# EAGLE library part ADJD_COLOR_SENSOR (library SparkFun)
Color Light Sensor ADJD-S371 from Avago. Digital RGB light sensor (I2C) with on-board white LED. Not quite proven footprint or schematic component. SKU: COM-08618

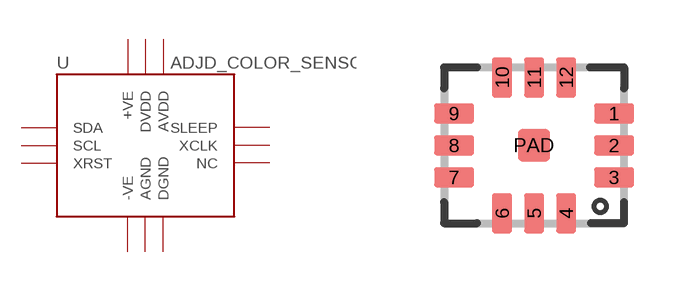
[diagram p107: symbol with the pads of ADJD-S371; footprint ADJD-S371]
Designator prefix -

## ADJD_COLOR_SENSOR_SMD  [ADJD-S371]
1  -VE
2  NC
3  +VE
4  SDA
5  DVDD
6  SCL
7  AVDD
8  SLEEP
9  AGND
10  XRST
11  DGND
12  XCLK

## Footprint ADJD-S371 (pad centres in mm)
smd 1 x 0.5: 1 2,0.8; 2 2,0; 3 2,-0.8; 7 -2,-0.8; 8 -2,0; 9 -2,0.8
smd 0.5 x 1: 4 0.8,-1.7; 5 0,-1.7; 6 -0.8,-1.7; 10 -0.8,1.7; 11 0,1.7; 12 0.8,1.7
smd 0.8 x 0.8: PAD 0,0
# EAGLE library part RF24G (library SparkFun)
RF24G Header This is the header for connections to the RF24G Transceiver (SparkFun Electronics SKU: WRL-00151), used in the Breakout Board for RF24G Transceiver (SparkFun Electronics SKU: BOB-00196). This footprint has not yet been proven in production.

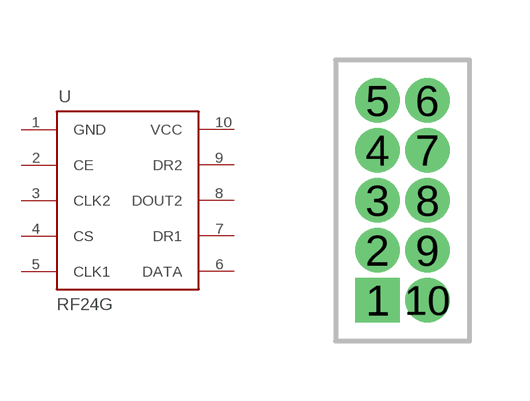
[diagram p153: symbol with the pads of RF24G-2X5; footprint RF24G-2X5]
Designator prefix -

## RF24G  [RF24G-2X5]
1  GND
2  CE
3  CLK2
4  CS
5  CLK1
6  DATA
7  DR1
8  DOUT2
9  DR2
10  VCC

## Footprint RF24G-2X5 (pad centres in mm)
test
drill 0.6 pad 0.965 square: 1 1.047,1.021
drill 0.6 pad 0.965 round: 2 1.047,2.271; 3 1.047,3.521; 4 1.047,4.771; 5 1.047,6.021; 6 2.297,6.021; 7 2.297,4.771; 8 2.297,3.521; 9 2.297,2.271; 10 2.297,1.021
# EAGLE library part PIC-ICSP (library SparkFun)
ISCP Programming connector for UAV, UBW Kit, etc.

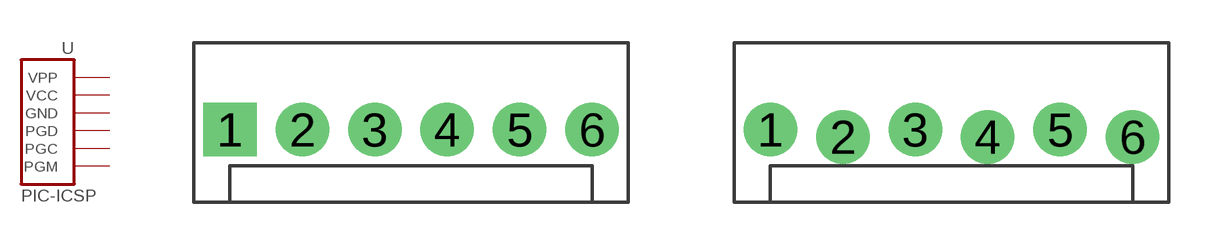
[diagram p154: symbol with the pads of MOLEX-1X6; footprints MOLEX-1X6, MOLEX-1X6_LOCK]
Designator prefix -

## PIC-ICSPPTH  [MOLEX-1X6]
1  PGM
2  PGC
3  PGD
4  GND
5  VCC
6  VPP

## PIC-ICSPPOLAR_LOCK  [MOLEX-1X6_LOCK]
Pads as for MOLEX-1X6

## Footprint MOLEX-1X6 (pad centres in mm)
drill 1.016 pad 1.88 square: 1 0,0
drill 1.016 pad 1.88 round: 2 2.54,0; 3 5.08,0; 4 7.62,0; 5 10.16,0; 6 12.7,0

## Footprint MOLEX-1X6_LOCK (pad centres in mm)
This footprint was designed to help hold the alignment of a through-hole component (i.e. 6-pin header) while soldering it into place. You may notice that each hole has been shifted either up or down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
drill 1.016 pad 1.88 round: 1 0,0; 2 2.54,-0.254; 3 5.08,0; 4 7.62,-0.254; 5 10.16,0; 6 12.7,-0.254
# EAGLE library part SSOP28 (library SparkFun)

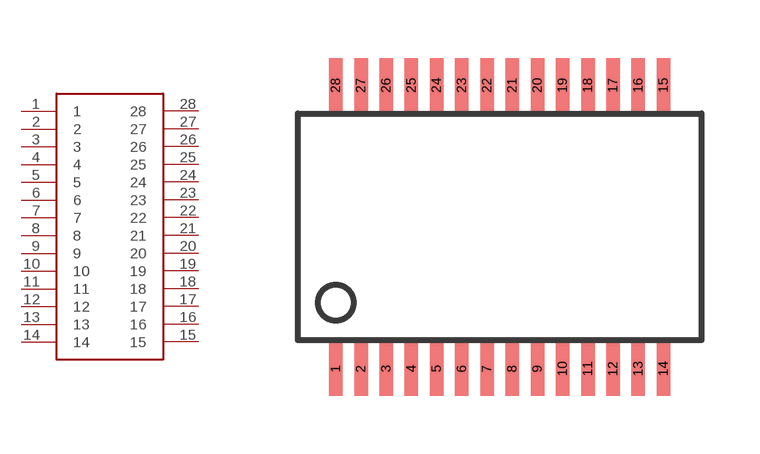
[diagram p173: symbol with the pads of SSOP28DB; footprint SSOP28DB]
Designator prefix -

## SSOP28  [SSOP28DB]
1  1
2  2
3  3
4  4
5  5
6  6
7  7
8  8
9  9
10  10
11  11
12  12
13  13
14  14
15  15
16  16
17  17
18  18
19  19
20  20
21  21
22  22
23  23
24  24
25  25
26  26
27  27
28  28

## Footprint SSOP28DB (pad centres in mm)
Small Shrink Outline Package
smd 0.348 x 1.397: 1 -4.225,-3.656; 2 -3.575,-3.656; 3 -2.925,-3.656; 4 -2.275,-3.656; 5 -1.625,-3.656; 6 -0.975,-3.656; 7 -0.325,-3.656; 8 0.325,-3.656; 9 0.975,-3.656; 10 1.625,-3.656; 11 2.275,-3.656; 12 2.925,-3.656; 13 3.575,-3.656; 14 4.225,-3.656; 15 4.225,3.656; 16 3.575,3.656; 17 2.925,3.656; 18 2.275,3.656; 19 1.625,3.656; 20 0.975,3.656; 21 0.325,3.656; 22 -0.325,3.656; 23 -0.975,3.656; 24 -1.625,3.656; 25 -2.275,3.656; 26 -2.925,3.656; 27 -3.575,3.656; 28 -4.225,3.656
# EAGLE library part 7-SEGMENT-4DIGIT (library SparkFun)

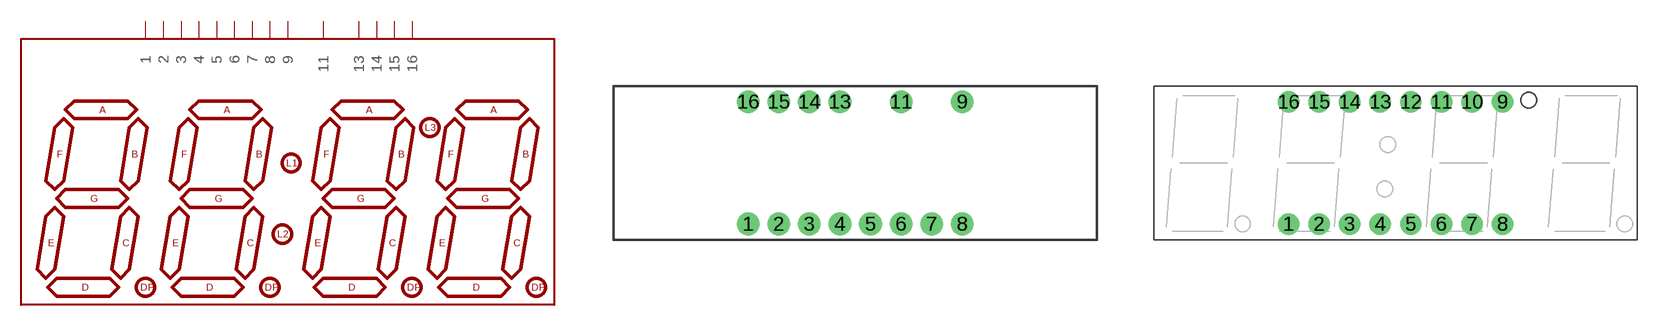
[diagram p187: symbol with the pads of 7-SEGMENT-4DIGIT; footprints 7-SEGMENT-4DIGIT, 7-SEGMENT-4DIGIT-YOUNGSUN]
Designator prefix -

## 7-SEGMENT-4DIGITPTH  [7-SEGMENT-4DIGIT]
1  1
2  2
3  3
4  4
5  5
6  6
7  7
8  8
9  9
11  11
13  13
14  14
15  15
16  16

## 7-SEGMENT-4DIGIT  [7-SEGMENT-4DIGIT-YOUNGSUN]
Pads as for 7-SEGMENT-4DIGIT

## 7-SEGMENT-4DIGITFOR_POGOBED_ONLY  [7-SEGMENT-4DIGIT_LONGPADS_FOR_POGOBED]
Pads as for 7-SEGMENT-4DIGIT

## Footprint 7-SEGMENT-4DIGIT (pad centres in mm)
drill 0.9 pad 1.88 round: 1 -8.89,-5.08; 2 -6.35,-5.08; 3 -3.81,-5.08; 4 -1.27,-5.08; 5 1.27,-5.08; 6 3.81,-5.08; 7 6.35,-5.08; 8 8.89,-5.08; 9 8.89,5.08; 11 3.81,5.08; 13 -1.27,5.08; 14 -3.81,5.08; 15 -6.35,5.08; 16 -8.89,5.08

## Footprint 7-SEGMENT-4DIGIT-YOUNGSUN (pad centres in mm)
This is a package for the 4-digit 7-segment RED LED from Young Sun.
drill 0.8 pad 1.778 round: 1 -8.89,-5.08; 2 -6.35,-5.08; 3 -3.81,-5.08; 4 -1.27,-5.08; 5 1.27,-5.08; 6 3.81,-5.08; 7 6.35,-5.08; 8 8.89,-5.08; 9 8.89,5.08; 10 6.35,5.08; 11 3.81,5.08; 12 1.27,5.08; 13 -1.27,5.08; 14 -3.81,5.08; 15 -6.35,5.08; 16 -8.89,5.08

## Footprint 7-SEGMENT-4DIGIT_LONGPADS_FOR_POGOBED (pad centres in mm)
drill 1.016 pad 1.88 long: 1 -8.89,-5.08; 2 -6.35,-5.08; 3 -3.81,-5.08; 4 -1.27,-5.08; 5 1.27,-5.08; 6 3.81,-5.08; 7 6.35,-5.08; 8 8.89,-5.08; 9 8.89,5.08; 11 3.81,5.08; 13 -1.27,5.08; 14 -3.81,5.08; 15 -6.35,5.08; 16 -8.89,5.08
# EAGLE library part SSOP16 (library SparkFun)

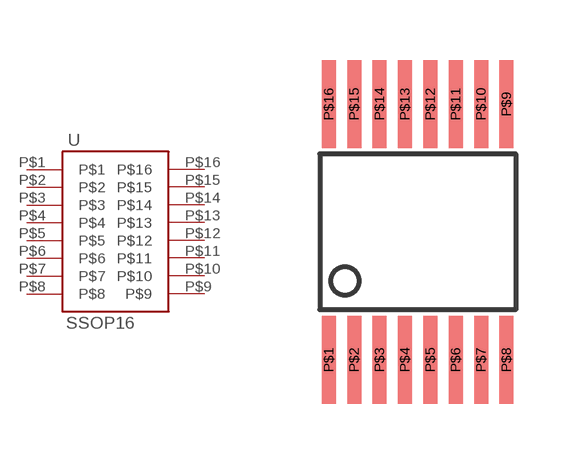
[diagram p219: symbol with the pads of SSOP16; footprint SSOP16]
Designator prefix -

## SSOP16  [SSOP16]
P$1  P$1
P$2  P$2
P$3  P$3
P$4  P$4
P$5  P$5
P$6  P$6
P$7  P$7
P$8  P$8
P$9  P$9
P$10  P$10
P$11  P$11
P$12  P$12
P$13  P$13
P$14  P$14
P$15  P$15
P$16  P$16

## Footprint SSOP16 (pad centres in mm)
smd 0.35 x 2.2: P$1 -2.223,-3.2; P$2 -1.587,-3.2; P$3 -0.953,-3.2; P$4 -0.318,-3.2; P$5 0.318,-3.2; P$6 0.953,-3.2; P$7 1.587,-3.2; P$8 2.223,-3.2; P$9 2.223,3.2; P$10 1.587,3.2; P$11 0.953,3.2; P$12 0.318,3.2; P$13 -0.318,3.2; P$14 -0.953,3.2; P$15 -1.587,3.2; P$16 -2.223,3.2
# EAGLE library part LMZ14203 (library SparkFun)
LMZ14203 3A, Simple Switcher Power Module with 42V Maximum Input

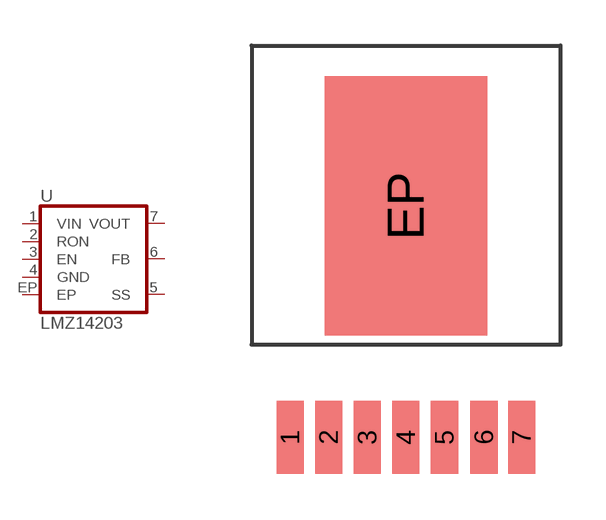
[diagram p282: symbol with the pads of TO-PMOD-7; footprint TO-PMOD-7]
Designator prefix U

## LMZ14203  [TO-PMOD-7]
1  VIN
2  RON
3  EN
4  GND
5  SS
6  FB
7  VOUT
EP  EP

## Footprint TO-PMOD-7 (pad centres in mm)
7-Lead package for National voltage switchers (LMZ14203)
smd 0.89 x 2.41: 1 -3.81,-7.63; 2 -2.54,-7.63; 3 -1.27,-7.63; 4 0,-7.63; 5 1.27,-7.63; 6 2.57,-7.63; 7 3.81,-7.63
smd 5.35 x 8.54: EP 0,0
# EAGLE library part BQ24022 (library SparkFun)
TI BQ24022 Single-chip, Li-ion and Li-pol charger IC with autonomous USB-port and AC-adapter supply management. Datasheet: http://focus.ti.com/lit/ds/symlink/bq24022.pdf Unproven Last modified: 8/16/10

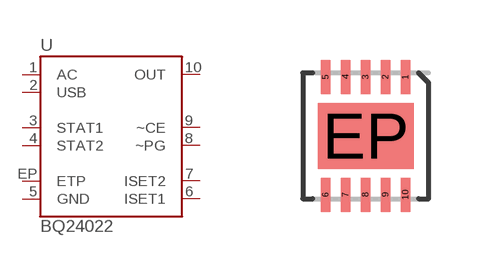
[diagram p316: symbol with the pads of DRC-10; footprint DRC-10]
Designator prefix U

## BQ24022  [DRC-10]
1  AC
2  USB
3  STAT1
4  STAT2
5  GND
6  ISET1
7  ISET2
8  ~PG
9  ~CE
10  OUT
EP  ETP

## Footprint DRC-10 (pad centres in mm)
10-pin QFN/SON package Package Type: SON Package Drawing: DRC Pitch: 0.5mm Overall Dimensions: 3.15x3.15mm Pins: 10 (+1 exposed heatsink pin) Related ICs: TI's BQ2402x -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
smd 0.23 x 0.85: 1 1,1.475; 2 0.5,1.475; 3 0,1.475; 4 -0.5,1.475; 5 -1,1.475; 6 -1,-1.475; 7 -0.5,-1.475; 8 0,-1.475; 9 0.5,-1.475; 10 1,-1.475
smd 2.4 x 1.65: EP 0,0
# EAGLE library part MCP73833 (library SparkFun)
Microchip MCP73833 Stand-alone Linear Li-ion/Li-polymer Charge Management Controller Packages: DFN-10, MSOP-10 Last modified: 8/17/10 Unproven!

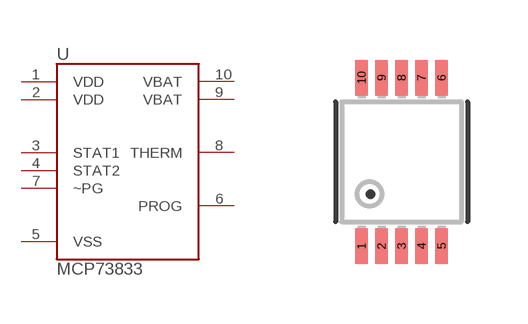
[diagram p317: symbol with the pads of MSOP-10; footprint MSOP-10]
Designator prefix U

## MCP73833  [MSOP-10]
1  VDD
2  VDD
3  STAT1
4  STAT2
5  VSS
6  PROG
7  ~PG
8  THERM
9  VBAT
10  VBAT

## Footprint MSOP-10 (pad centres in mm)
smd 0.305 x 0.889: 1 -1,-2.11; 2 -0.5,-2.11; 3 0,-2.11; 4 0.5,-2.11; 5 1,-2.11; 6 1,2.11; 7 0.5,2.11; 8 0,2.11; 9 -0.5,2.11; 10 -1,2.11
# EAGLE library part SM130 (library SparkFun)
13.56MHz RFID Mifare Read/Write Module

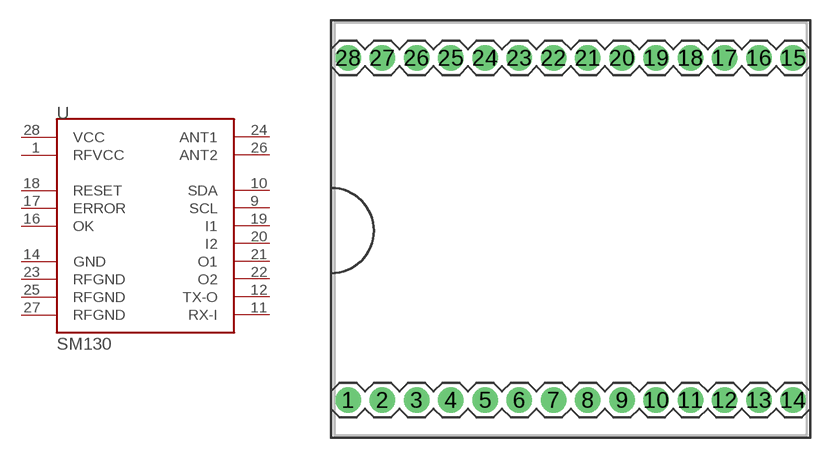
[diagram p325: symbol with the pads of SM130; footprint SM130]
Designator prefix U

## SM130  [SM130]
1  RFVCC
9  SCL
10  SDA
11  RX-I
12  TX-O
14  GND
16  OK
17  ERROR
18  RESET
19  I1
20  I2
21  O1
22  O2
23  RFGND
24  ANT1
25  RFGND
26  ANT2
27  RFGND
28  VCC

## Footprint SM130 (pad centres in mm)
30-pin DIL with 100mil spacing between headers
drill 1.016 pad 1.88 round: 1 -17.78,-12.7; 2 -15.24,-12.7; 3 -12.7,-12.7; 4 -10.16,-12.7; 5 -7.62,-12.7; 6 -5.08,-12.7; 7 -2.54,-12.7; 8 0,-12.7; 9 2.54,-12.7; 10 5.08,-12.7; 11 7.62,-12.7; 12 10.16,-12.7; 13 12.7,-12.7; 14 15.24,-12.7; 15 15.24,12.7; 16 12.7,12.7; 17 10.16,12.7; 18 7.62,12.7; 19 5.08,12.7; 20 2.54,12.7; 21 0,12.7; 22 -2.54,12.7; 23 -5.08,12.7; 24 -7.62,12.7; 25 -10.16,12.7; 26 -12.7,12.7; 27 -15.24,12.7; 28 -17.78,12.7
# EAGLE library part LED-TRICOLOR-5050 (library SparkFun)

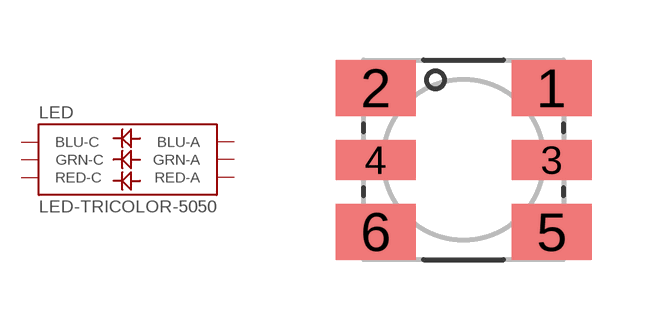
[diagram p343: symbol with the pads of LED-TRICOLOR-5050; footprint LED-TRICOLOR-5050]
Designator prefix LED

## LED-TRICOLOR-5050  [LED-TRICOLOR-5050]
1  GRN-A
2  RED-A
3  BLU-A
4  BLU-C
5  RED-C
6  GRN-C

## Footprint LED-TRICOLOR-5050 (pad centres in mm)
5050 SMD RGB LED 5.0mm x 5.0mm, 2.6mm thickness
smd 2 x 1.4: 1 2.2,1.8; 2 -2.2,1.8; 5 2.2,-1.8; 6 -2.2,-1.8
smd 2 x 1: 3 2.2,0; 4 -2.2,0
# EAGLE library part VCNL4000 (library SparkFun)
VNCL4000 Fully integrated proximity and ambient light sensor with infrared emitter and I2C interface

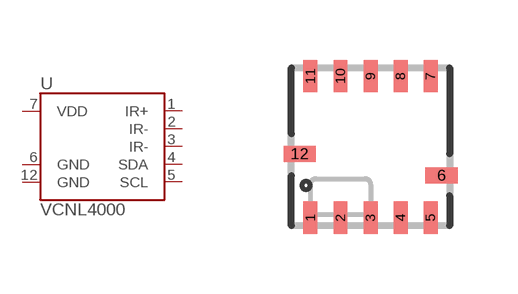
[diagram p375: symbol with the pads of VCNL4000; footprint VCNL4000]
Designator prefix U

## VCNL4000  [VCNL4000]
1  IR+
2  IR-
3  IR-
4  SDA
5  SCL
6  GND
7  VDD
12  GND

## Footprint VCNL4000 (pad centres in mm)
VCNL4000 Footprint For Vishay VNCL4000 proximity and ambient light sensor. Unproven
smd 0.35 x 0.805: 1 -1.5,-1.772; 2 -0.75,-1.772; 3 0,-1.772; 4 0.75,-1.772; 5 1.5,-1.772; 7 1.5,1.772; 8 0.75,1.772; 9 0,1.772; 10 -0.75,1.772; 11 -1.5,1.772
smd 0.805 x 0.4: 6 1.772,-0.715; 12 -1.772,-0.175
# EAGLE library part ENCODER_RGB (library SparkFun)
Illuminated Rotary Encoder w/ RGB LED and select switch EC12PLRGBSDVBF-D: http://top-up.so-buy.com/front/bin/ptdetail.phtml?Part=EC12PLRGBSDVBF-D

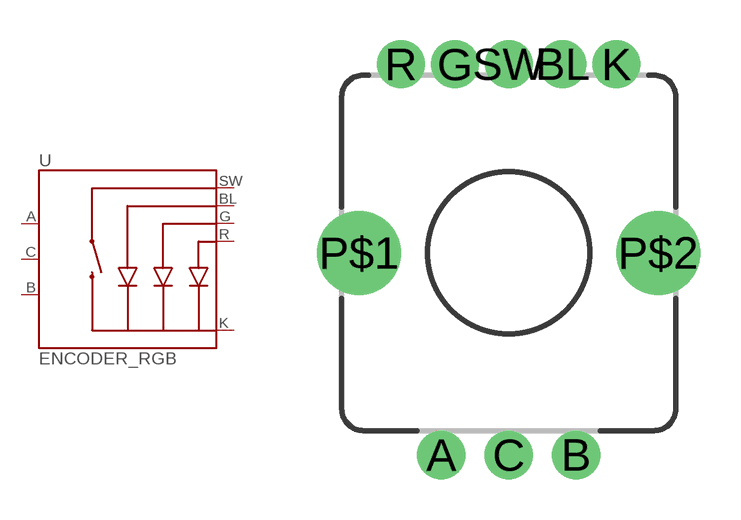
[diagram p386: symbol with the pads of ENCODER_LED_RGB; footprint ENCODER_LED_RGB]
Designator prefix U

## ENCODER_RGB  [ENCODER_LED_RGB]
A  A
B  B
BL  BL  pas
C  C
G  G  pas
K  K  pas
R  R  pas
SW  SW  pas

## Footprint ENCODER_LED_RGB (pad centres in mm)
drill 1.1 pad 1.8 round: A -2.5,-7.5; B 2.5,-7.5; C 0,-7.5
drill 1.1 pad 1.778 round: BL 2,7; G -2,7; K 4,7; R -4,7; SW 0,7
drill 2.1 round: P$1 -5.55,0; P$2 5.55,0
